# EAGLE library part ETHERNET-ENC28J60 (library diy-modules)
Ethernet Module based on ENC28J60 chip Click here to find device on ebay.com Note: There are many variants. Search for the proper version.

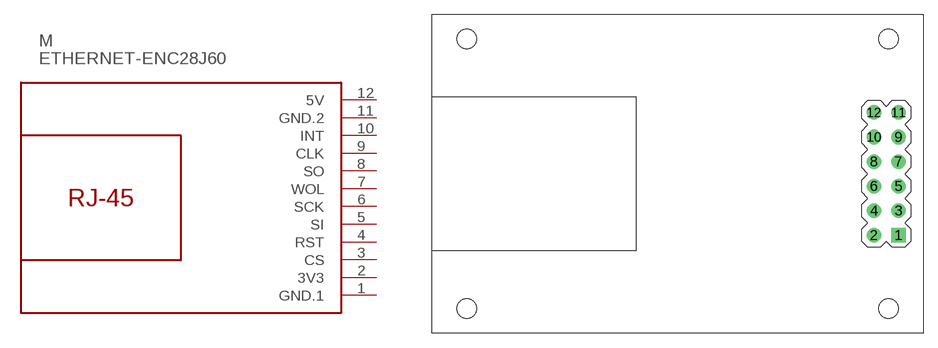
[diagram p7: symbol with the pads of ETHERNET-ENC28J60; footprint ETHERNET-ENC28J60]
Designator prefix M

## ETHERNET-ENC28J60  [ETHERNET-ENC28J60]
1  GND.1  pwr
2  3V3  pwr
3  CS
4  RST
5  SI
6  SCK
7  WOL
8  SO
9  CLK
10  INT
11  GND.2  pwr
12  5V  pwr

## Footprint ETHERNET-ENC28J60 (pad centres in mm)
Ethernet Module based on ENC28J60 chip
drill 1 square: 1 22.86,-6.35
drill 1: 2 20.32,-6.35; 3 22.86,-3.81; 4 20.32,-3.81; 5 22.86,-1.27; 6 20.32,-1.27; 7 22.86,1.27; 8 20.32,1.27; 9 22.86,3.81; 10 20.32,3.81; 11 22.86,6.35; 12 20.32,6.35
hole 2 at -21.844,13.97
hole 2 at 21.844,13.97
hole 2 at -21.844,-13.97
hole 2 at 21.844,-13.97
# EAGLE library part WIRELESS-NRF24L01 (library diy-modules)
2.4 GHz Wireless Module based on NRF24L01 chip More details available here: http://www.electrodragon.com/w/NRF24L01 Click here to find device on ebay.com

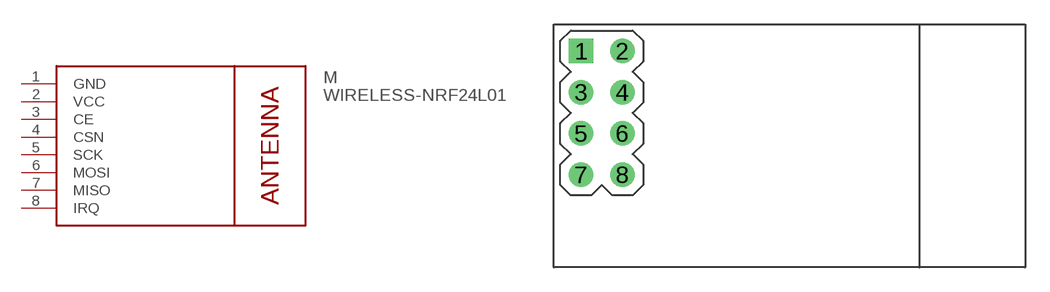
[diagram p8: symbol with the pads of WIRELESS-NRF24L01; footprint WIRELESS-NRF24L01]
Designator prefix M

## WIRELESS-NRF24L01  [WIRELESS-NRF24L01]
1  GND  pwr
2  VCC  pwr
3  CE
4  CSN
5  SCK
6  MOSI
7  MISO
8  IRQ

## Footprint WIRELESS-NRF24L01 (pad centres in mm)
2.4 GHz Wireless Module based on NRF24L01 chip
drill 1 square: 1 -12.7,6.35
drill 1: 2 -10.16,6.35; 3 -12.7,3.81; 4 -10.16,3.81; 5 -12.7,1.27; 6 -10.16,1.27; 7 -12.7,-1.27; 8 -10.16,-1.27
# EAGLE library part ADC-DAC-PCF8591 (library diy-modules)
4-Channel ADC and 1-Channel DAC Module based on PCF8591 chip More details available here: https://brainfyre.wordpress.com/2012/10/25/pcf8591-yl-40-ad-da-module-review/ Click here to find device on ebay.com

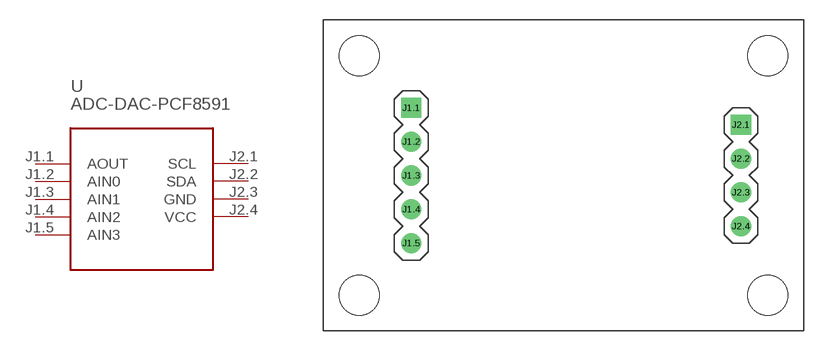
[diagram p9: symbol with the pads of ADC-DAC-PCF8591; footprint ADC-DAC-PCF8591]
Designator prefix -

## ADC-DAC-PCF8591  [ADC-DAC-PCF8591]
J1.1  AOUT
J1.2  AIN0
J1.3  AIN1
J1.4  AIN2
J1.5  AIN3
J2.1  SCL
J2.2  SDA
J2.3  GND  pwr
J2.4  VCC  pwr

## Footprint ADC-DAC-PCF8591 (pad centres in mm)
4-Channel ADC and 1-Channel DAC Module based on PCF8591 chip
drill 1 square: J1.1 -11.43,5.08; J2.1 13.335,3.81
drill 1: J1.2 -11.43,2.54; J1.3 -11.43,0; J1.4 -11.43,-2.54; J1.5 -11.43,-5.08; J2.2 13.335,1.27; J2.3 13.335,-1.27; J2.4 13.335,-3.81
hole 3 at -15.35,9
hole 3 at 15.35,9
hole 3 at -15.35,-9
hole 3 at 15.35,-9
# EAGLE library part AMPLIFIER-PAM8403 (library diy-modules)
Stereo Class-D 3W Audio Amplifier based on PAM8403 chip More details available here: http://artofcircuits.com/product/pam8403-5v-two-channel-stereo-mini-class-d-3w3w-audio-amplifier Click here to find device on ebay.com

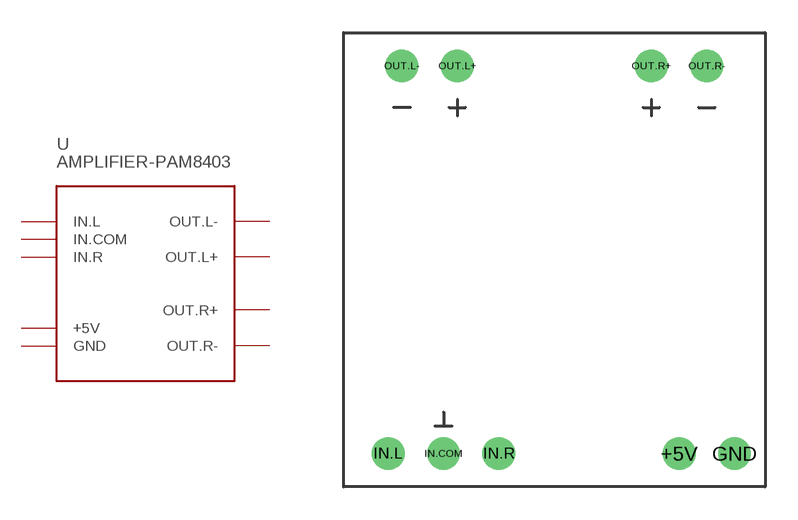
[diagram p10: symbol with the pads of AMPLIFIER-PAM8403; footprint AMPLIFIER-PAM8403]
Designator prefix -

## AMPLIFIER-PAM8403  [AMPLIFIER-PAM8403]
+5V  +5V  pwr
GND  GND  pwr
IN.COM  IN.COM  in
IN.L  IN.L  in
IN.R  IN.R
OUT.L+  OUT.L+  out
OUT.L-  OUT.L-  out
OUT.R+  OUT.R+  out
OUT.R-  OUT.R-  out

## Footprint AMPLIFIER-PAM8403 (pad centres in mm)
Stereo Class-D 3W Audio Amplifier based on PAM8403 chip
drill 1: +5V 5.715,-8.89; GND 8.255,-8.89; IN.COM -5.08,-8.89; IN.L -7.62,-8.89; IN.R -2.54,-8.89; OUT.L+ -4.445,8.89; OUT.L- -6.985,8.89; OUT.R+ 4.445,8.89; OUT.R- 6.985,8.89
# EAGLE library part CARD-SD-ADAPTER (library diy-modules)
Full Size SD Card Adapter Module with onboard 3.3V regulator Guide describing how to use SD card with Arduino is available here: https://www.arduino.cc/en/Reference/SDCardNotes Click here to find device on ebay.com

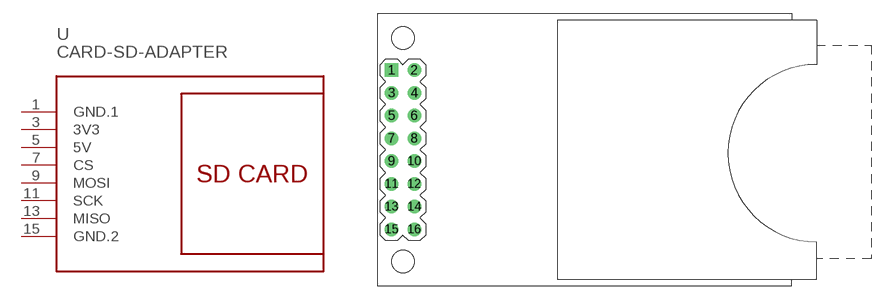
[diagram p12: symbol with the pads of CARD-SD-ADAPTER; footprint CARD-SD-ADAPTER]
Designator prefix -

## CARD-SD-ADAPTER  [CARD-SD-ADAPTER]
1  GND.1  pwr
3  3V3  pwr
5  5V  pwr
7  CS
9  MOSI
11  SCK
13  MISO
15  GND.2  pwr

## Footprint CARD-SD-ADAPTER (pad centres in mm)
Full Size SD Card Adapter Module with onboard 3.3V regulator
drill 1 square: 1 -21.59,8.89
drill 1: 2 -19.05,8.89; 3 -21.59,6.35; 4 -19.05,6.35; 5 -21.59,3.81; 6 -19.05,3.81; 7 -21.59,1.27; 8 -19.05,1.27; 9 -21.59,-1.27; 10 -19.05,-1.27; 11 -21.59,-3.81; 12 -19.05,-3.81; 13 -21.59,-6.35; 14 -19.05,-6.35; 15 -21.59,-8.89; 16 -19.05,-8.89
hole 2.5 at -20.32,12.5
hole 2.5 at -20.32,-12.5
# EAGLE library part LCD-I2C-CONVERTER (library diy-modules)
I2C Bus to 4-Bit Parallel LCD Interface with LED backlight driver

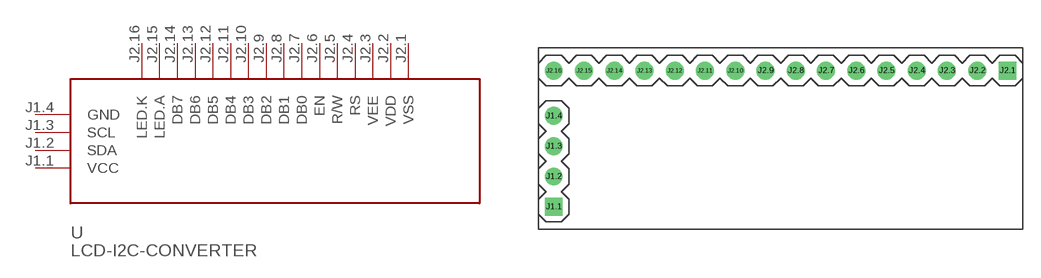
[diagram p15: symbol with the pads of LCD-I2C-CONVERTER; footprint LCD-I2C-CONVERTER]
Designator prefix -

## LCD-I2C-CONVERTER  [LCD-I2C-CONVERTER]
J1.1  VCC  pwr
J1.2  SDA
J1.3  SCL
J1.4  GND  pwr
J2.1  VSS
J2.2  VDD
J2.3  VEE
J2.4  RS
J2.5  R/W
J2.6  EN
J2.7  DB0
J2.8  DB1
J2.9  DB2
J2.10  DB3
J2.11  DB4
J2.12  DB5
J2.13  DB6
J2.14  DB7
J2.15  LED.A
J2.16  LED.K

## Footprint LCD-I2C-CONVERTER (pad centres in mm)
I2C Bus to 4-Bit Parallel LCD Interface with LED backlight driver
drill 1 square: J1.1 -19.05,-5.08; J2.1 19.05,6.35
drill 1: J1.2 -19.05,-2.54; J1.3 -19.05,0; J1.4 -19.05,2.54; J2.2 16.51,6.35; J2.3 13.97,6.35; J2.4 11.43,6.35; J2.5 8.89,6.35; J2.6 6.35,6.35; J2.7 3.81,6.35; J2.8 1.27,6.35; J2.9 -1.27,6.35; J2.10 -3.81,6.35; J2.11 -6.35,6.35; J2.12 -8.89,6.35; J2.13 -11.43,6.35; J2.14 -13.97,6.35; J2.15 -16.51,6.35; J2.16 -19.05,6.35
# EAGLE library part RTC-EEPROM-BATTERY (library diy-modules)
RTC Module with Battery and EEPROM based on DS1307 and AT24C32 chips More details available here: http://henrysbench.capnfatz.com/henrys-bench/arduino-sensors-and-input/arduino-tiny-rtc-d1307-tutorial/ Click here to find device on ebay.com

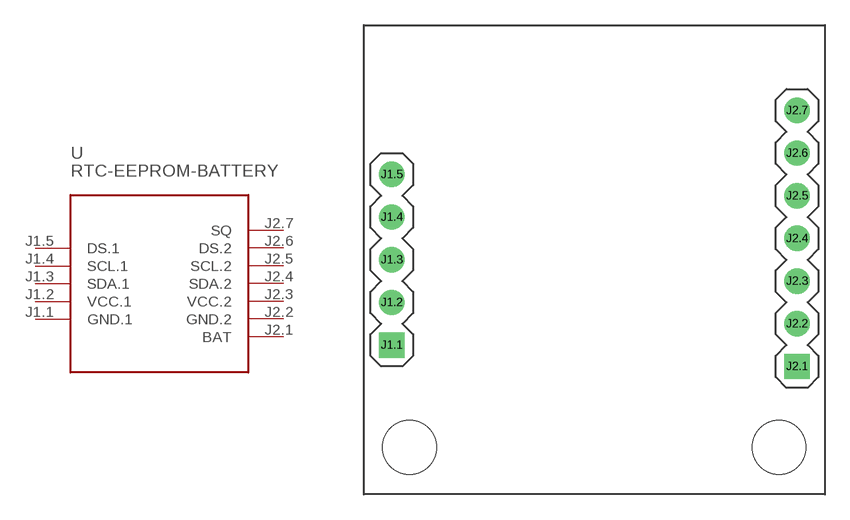
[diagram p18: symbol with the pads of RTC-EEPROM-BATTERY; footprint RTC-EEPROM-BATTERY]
Designator prefix -

## RTC-EEPROM-BATTERY  [RTC-EEPROM-BATTERY]
J1.1  GND.1  pwr
J1.2  VCC.1  pwr
J1.3  SDA.1
J1.4  SCL.1
J1.5  DS.1
J2.1  BAT
J2.2  GND.2  pwr
J2.3  VCC.2  pwr
J2.4  SDA.2
J2.5  SCL.2
J2.6  DS.2
J2.7  SQ

## Footprint RTC-EEPROM-BATTERY (pad centres in mm)
RTC Module with Battery and EEPROM based on DS1307 and AT24C32 chips
drill 1 square: J1.1 -12.065,-5.08; J2.1 12.065,-6.35
drill 1: J1.2 -12.065,-2.54; J1.3 -12.065,0; J1.4 -12.065,2.54; J1.5 -12.065,5.08; J2.2 12.065,-3.81; J2.3 12.065,-1.27; J2.4 12.065,1.27; J2.5 12.065,3.81; J2.6 12.065,6.35; J2.7 12.065,8.89
hole 3.2 at -11,-11.176
hole 3.2 at 11,-11.176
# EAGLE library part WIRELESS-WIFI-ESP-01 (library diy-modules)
Wireless Wi-Fi ESP-01 Module based on ESP8266 chip Click here to find device on ebay.com

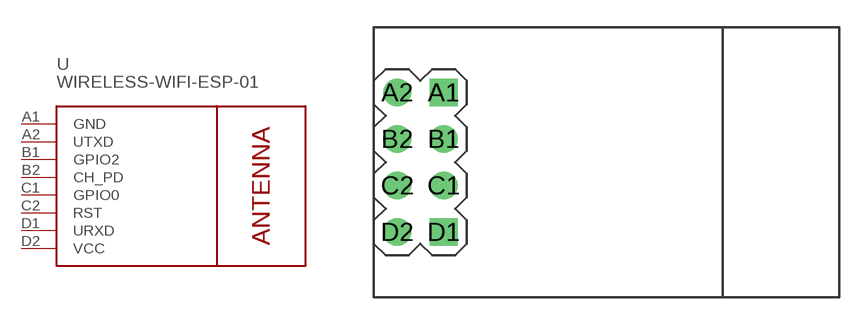
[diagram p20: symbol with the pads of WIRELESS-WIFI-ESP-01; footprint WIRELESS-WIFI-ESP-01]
Designator prefix -

## WIRELESS-WIFI-ESP-01  [WIRELESS-WIFI-ESP-01]
A1  GND  pwr
A2  UTXD
B1  GPIO2
B2  CH_PD
C1  GPIO0
C2  RST
D1  URXD
D2  VCC  pwr

## Footprint WIRELESS-WIFI-ESP-01 (pad centres in mm)
Wireless Wi-Fi ESP-01 Module based on ESP8266 chip
drill 1 square: A1 -8.89,3.81; D1 -8.89,-3.81
drill 1: A2 -11.43,3.81; B1 -8.89,1.27; B2 -11.43,1.27; C1 -8.89,-1.27; C2 -11.43,-1.27; D2 -11.43,-3.81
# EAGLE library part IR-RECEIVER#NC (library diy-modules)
IR Receiver Module without IR sensor connector

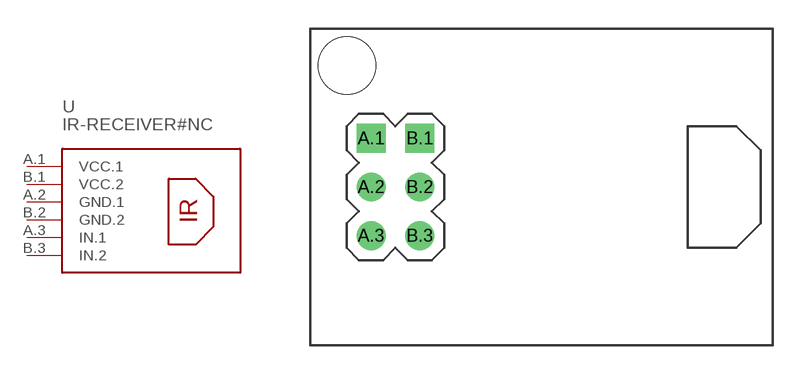
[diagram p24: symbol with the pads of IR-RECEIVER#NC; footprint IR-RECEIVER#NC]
Designator prefix -

## IR-RECEIVER#NC  [IR-RECEIVER#NC]
A.1  VCC.1
A.2  GND.1
A.3  IN.1
B.1  VCC.2
B.2  GND.2
B.3  IN.2

## Footprint IR-RECEIVER#NC (pad centres in mm)
IR Receiver Module Symbol wihtout IR sensor connector
drill 1 square: A.1 -8.89,2.54; B.1 -6.35,2.54
drill 1: A.2 -8.89,0; A.3 -8.89,-2.54; B.2 -6.35,0; B.3 -6.35,-2.54
hole 3 at -10.16,6.35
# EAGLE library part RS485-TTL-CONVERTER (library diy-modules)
RS485 to TTL converter based on MAX485 chip

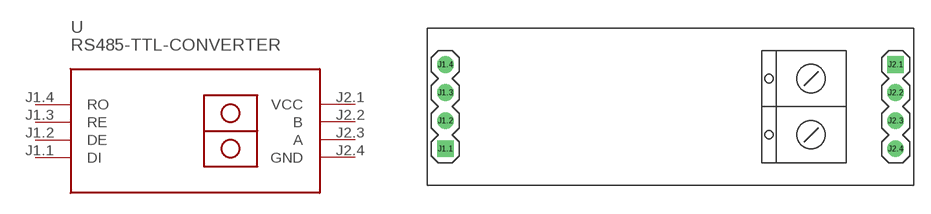
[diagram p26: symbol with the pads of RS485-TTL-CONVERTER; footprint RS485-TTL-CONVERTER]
Designator prefix -

## RS485-TTL-CONVERTER  [RS485-TTL-CONVERTER]
J1.1  DI  pas
J1.2  DE  pas
J1.3  RE  pas
J1.4  RO  pas
J2.1  VCC  pwr
J2.2  B  pas
J2.3  A  pas
J2.4  GND  pwr

## Footprint RS485-TTL-CONVERTER (pad centres in mm)
RS485 to TTL converter based on MAX485 chip
drill 1 square: J1.1 -20.32,-3.81; J2.1 20.32,3.81
drill 1: J1.2 -20.32,-1.27; J1.3 -20.32,1.27; J1.4 -20.32,3.81; J2.2 20.32,1.27; J2.3 20.32,-1.27; J2.4 20.32,-3.81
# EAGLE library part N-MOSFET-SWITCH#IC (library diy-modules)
Low Side N-MOSFET Switch with Optocoupler Device with connector pins Click here to find device on ebay.com

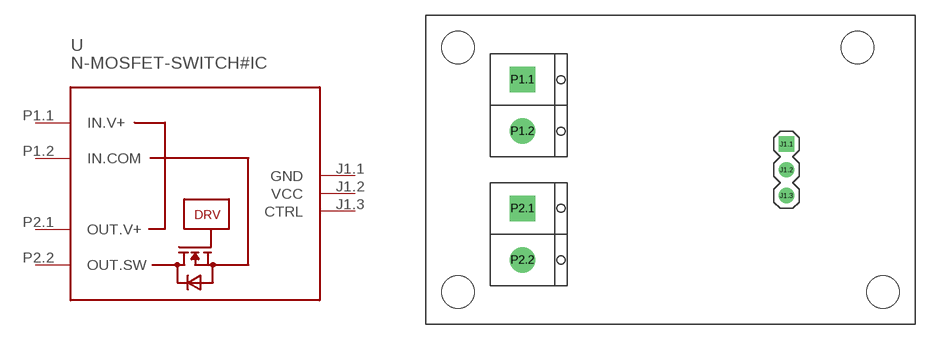
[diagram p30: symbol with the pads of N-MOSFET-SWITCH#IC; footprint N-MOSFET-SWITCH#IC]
Designator prefix -

## N-MOSFET-SWITCH#IC  [N-MOSFET-SWITCH#IC]
J1.1  GND  pwr
J1.2  VCC  pwr
J1.3  CTRL
P1.1  IN.V+  pwr
P1.2  IN.COM  pwr
P2.1  OUT.V+  pwr
P2.2  OUT.SW  pwr

## Footprint N-MOSFET-SWITCH#IC (pad centres in mm)
Low Side N-MOSFET Switch with Optocoupler Package with connector pins
drill 1 square: J1.1 11.43,2.54
drill 1: J1.2 11.43,0; J1.3 11.43,-2.54
drill 1.2 pad 2.5 square: P1.1 -14.605,8.89; P2.1 -14.605,-3.81
drill 1.2 pad 2.5: P1.2 -14.605,3.81; P2.2 -14.605,-8.89
hole 3.2 at -20.955,12.065
hole 3.2 at 18.415,12.065
hole 3.2 at 20.955,-12.065
hole 3.2 at -20.955,-12.065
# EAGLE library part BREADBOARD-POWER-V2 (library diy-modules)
Breadboard Power Adapter with onboard 3.3V and 5V regulators Click here to find device on ebay.com

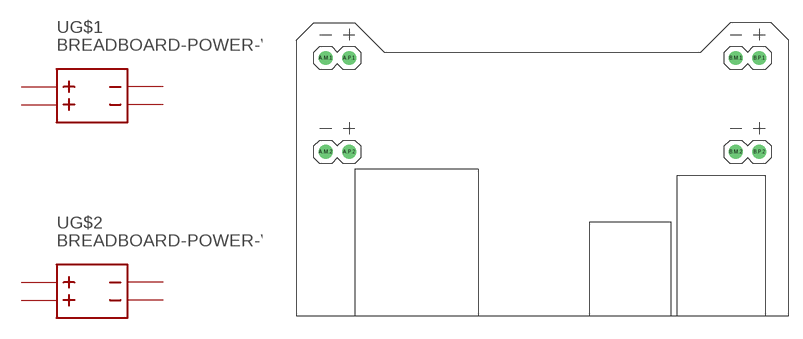
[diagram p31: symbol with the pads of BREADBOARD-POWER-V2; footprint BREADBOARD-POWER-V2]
Designator prefix -; gates G$1=BREADBOARD-POWER-V2 G$2=BREADBOARD-POWER-V2

## BREADBOARD-POWER-V2  [BREADBOARD-POWER-V2]
A.M.1  G$1:M.1
A.M.2  G$1:M.2
A.P.1  G$1:P.1
A.P.2  G$1:P.2
B.M.1  G$2:M.1
B.M.2  G$2:M.2
B.P.1  G$2:P.1
B.P.2  G$2:P.2

## Footprint BREADBOARD-POWER-V2 (pad centres in mm)
Breadboard Power Adapter with onboard 3.3V and 5V regulators
drill 1: A.M.1 -23.495,12.065; A.M.2 -23.495,1.905; A.P.1 -20.955,12.065; A.P.2 -20.955,1.905; B.M.1 20.955,12.065; B.M.2 20.955,1.905; B.P.1 23.495,12.065; B.P.2 23.495,1.905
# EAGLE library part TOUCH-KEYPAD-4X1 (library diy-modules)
4 Channel Capacitive Touch Keypad Click here to find device on ebay.com

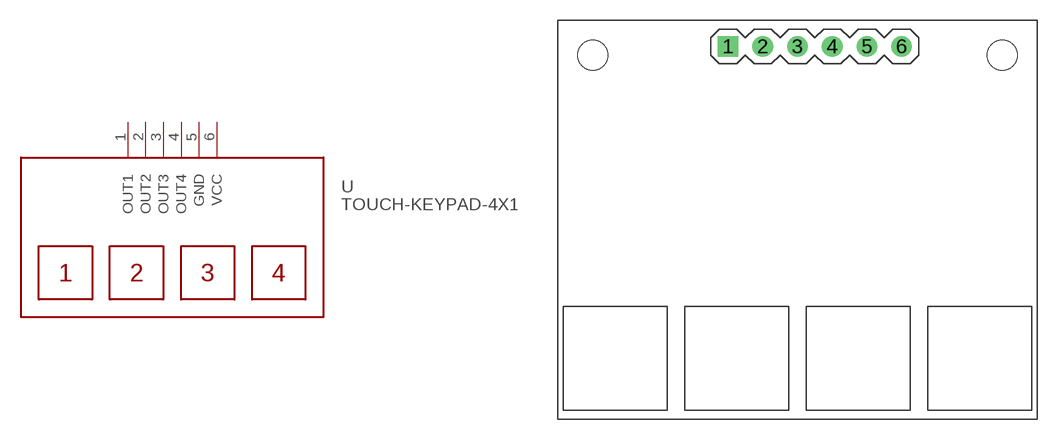
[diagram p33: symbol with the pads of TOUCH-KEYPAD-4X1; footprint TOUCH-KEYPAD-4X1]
Designator prefix -

## TOUCH-KEYPAD-4X1  [TOUCH-KEYPAD-4X1]
1  OUT1
2  OUT2
3  OUT3
4  OUT4
5  GND  pwr
6  VCC  pwr

## Footprint TOUCH-KEYPAD-4X1 (pad centres in mm)
4 Channel Capacitive Touch Keypad
drill 1 square: 1 -5.08,12.7
drill 1: 2 -2.54,12.7; 3 0,12.7; 4 2.54,12.7; 5 5.08,12.7; 6 7.62,12.7
hole 2.2 at -14.986,12.065
hole 2.2 at 14.986,12.065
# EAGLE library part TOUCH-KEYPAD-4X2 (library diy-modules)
8 Channel Capacitive Touch Keypad Click here to find device on ebay.com

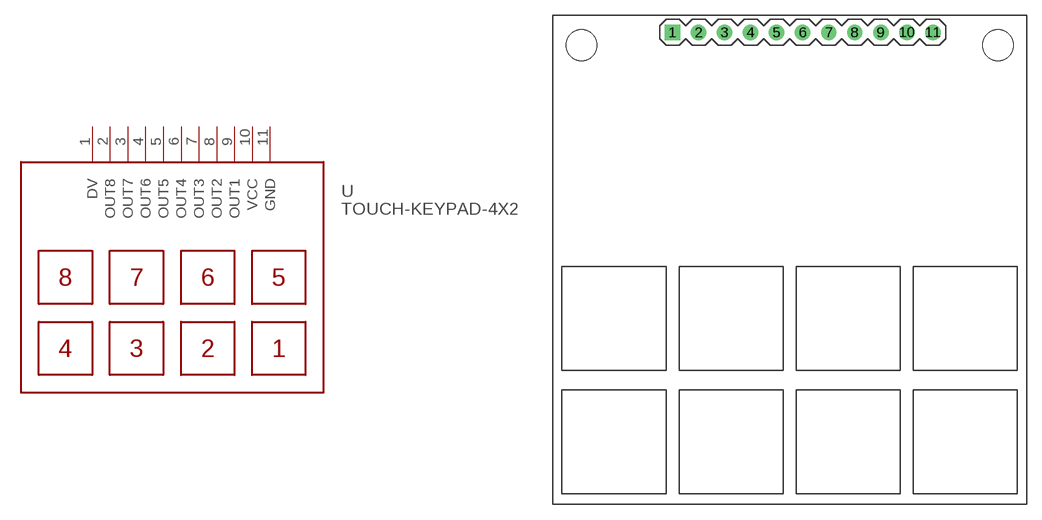
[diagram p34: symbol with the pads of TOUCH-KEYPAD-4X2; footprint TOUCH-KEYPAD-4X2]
Designator prefix -

## TOUCH-KEYPAD-4X2  [TOUCH-KEYPAD-4X2]
1  DV
2  OUT8
3  OUT7
4  OUT6
5  OUT5
6  OUT4
7  OUT3
8  OUT2
9  OUT1
10  VCC  pwr
11  GND  pwr

## Footprint TOUCH-KEYPAD-4X2 (pad centres in mm)
8 Channel Capacitive Touch Keypad
drill 1 square: 1 -11.43,22.225
drill 1: 2 -8.89,22.225; 3 -6.35,22.225; 4 -3.81,22.225; 5 -1.27,22.225; 6 1.27,22.225; 7 3.81,22.225; 8 6.35,22.225; 9 8.89,22.225; 10 11.43,22.225; 11 13.97,22.225
hole 3 at -20.32,20.955
hole 3 at 20.32,20.955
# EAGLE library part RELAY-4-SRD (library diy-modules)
4-Channel Relay Module based on SRD-05VDC-SL-C relays Click here to find device on ebay.com

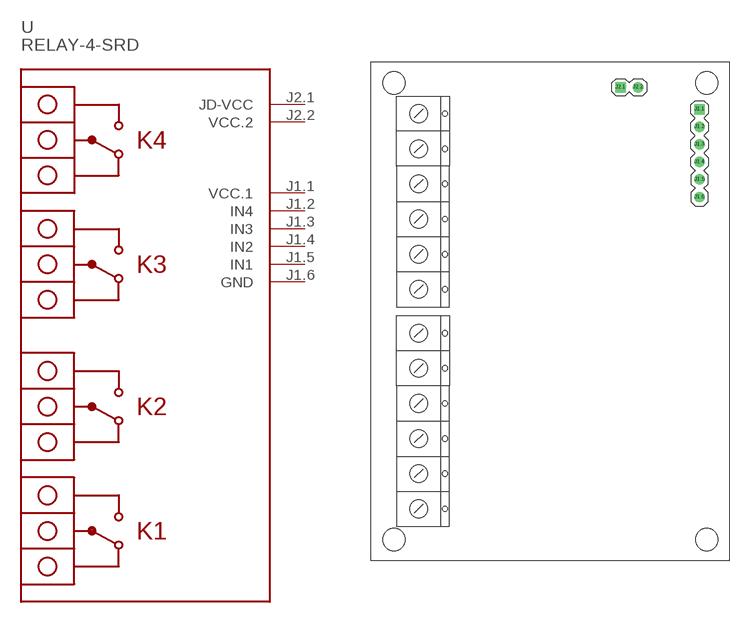
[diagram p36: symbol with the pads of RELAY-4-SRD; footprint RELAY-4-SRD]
Designator prefix -

## RELAY-4-SRD  [RELAY-4-SRD]
J1.1  VCC.1  pwr
J1.2  IN4
J1.3  IN3
J1.4  IN2
J1.5  IN1
J1.6  GND  pwr
J2.1  JD-VCC
J2.2  VCC.2  pwr

## Footprint RELAY-4-SRD (pad centres in mm)
4-Channel Relay Module based on SRD-05VDC-SL-C relays
drill 1 square: J1.1 21.59,29.21; J2.1 10.16,32.385
drill 1: J1.2 21.59,26.67; J1.3 21.59,24.13; J1.4 21.59,21.59; J1.5 21.59,19.05; J1.6 21.59,16.51; J2.2 12.7,32.385
hole 3.2 at -22.606,33.02
hole 3.2 at 22.606,33.02
hole 3.2 at 22.606,-33.02
hole 3.2 at -22.606,-33.02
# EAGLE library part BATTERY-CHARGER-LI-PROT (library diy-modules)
Lithium Battery 5V Charger with protection circuit More details available here: http://www.instructables.com/id/DIY-Lithium-ion-Battery-Charger/step4/TP4056-based-lithium-ion-battery-charger-module/ Click here to find device on ebay.com

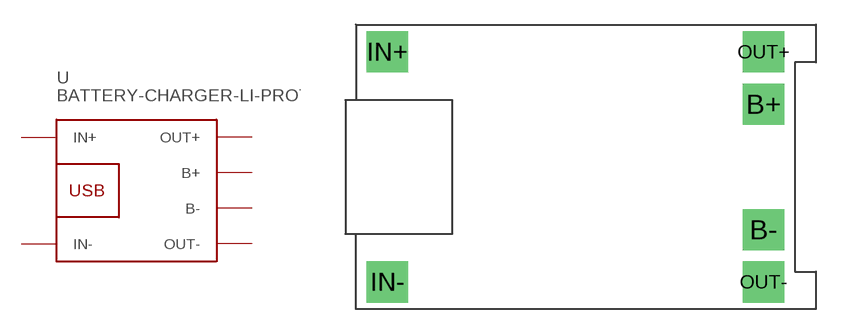
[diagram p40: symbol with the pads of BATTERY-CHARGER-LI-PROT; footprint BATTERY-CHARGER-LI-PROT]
Designator prefix -

## BATTERY-CHARGER-LI-PROT  [BATTERY-CHARGER-LI-PROT]
B+  B+
B-  B-
IN+  IN+
IN-  IN-
OUT+  OUT+
OUT-  OUT-

## Footprint BATTERY-CHARGER-LI-PROT (pad centres in mm)
Protected Lithium Battery 5V Charger with micro-USB connector
drill 1.2 pad 2.5 square: B+ 10.795,3.81; B- 10.795,-3.81; IN+ -12.065,6.985; IN- -12.065,-6.985; OUT+ 10.795,6.985; OUT- 10.795,-6.985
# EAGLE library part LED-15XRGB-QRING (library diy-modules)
15 LEDs RGB Quarter-Ring based on WS2812B More details about controlling WS2812B RGB LEDs are available here: https://learn.sparkfun.com/tutorials/ws2812-breakout-hookup-guide Click here to find device on ebay.com Note: Sold in packs of 4 pieces.

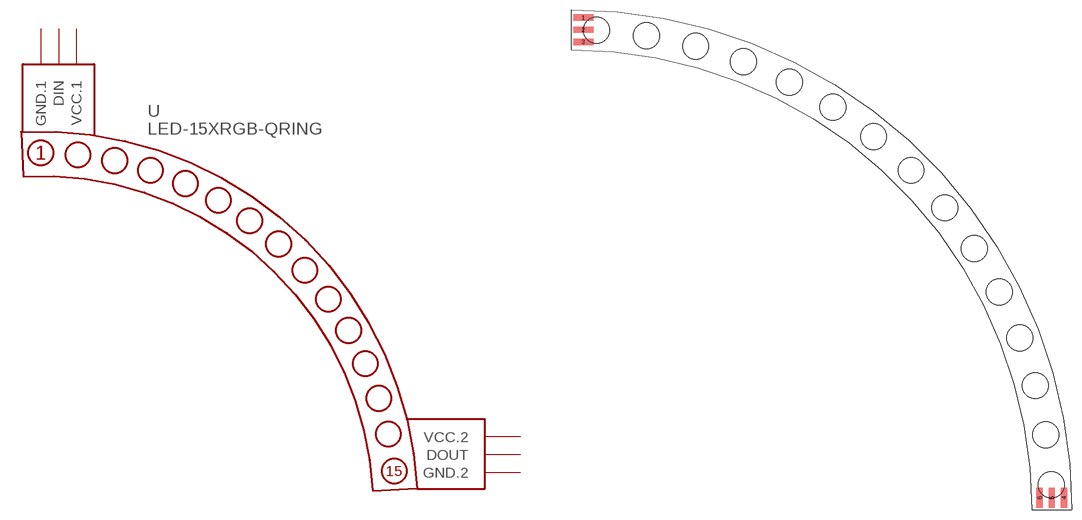
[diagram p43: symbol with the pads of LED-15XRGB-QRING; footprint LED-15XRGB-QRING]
Designator prefix -

## LED-15XRGB-QRING  [LED-15XRGB-QRING]
1  GND.1  pwr
2  DIN  in
3  VCC.1  pwr
4  GND.2  pwr
5  DOUT  out
6  VCC.2  pwr

## Footprint LED-15XRGB-QRING (pad centres in mm)
15 LEDs RGB Quarter-Ring based on WS2812B
smd 3.175 x 1.016: 1 1.905,77.47; 2 1.905,75.565; 3 1.905,73.66
smd 1.016 x 3.175: 4 77.47,1.905; 5 75.565,1.905; 6 73.66,1.905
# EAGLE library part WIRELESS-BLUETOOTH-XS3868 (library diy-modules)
Bluetooth Stereo Audio Module based on OVC3860 chip More details available here: http://artofcircuits.com/product/bluetooth-2-0-edr-stereo-audio-ovc3860-module-model-xs-3868 Click here to find device on ebay.com

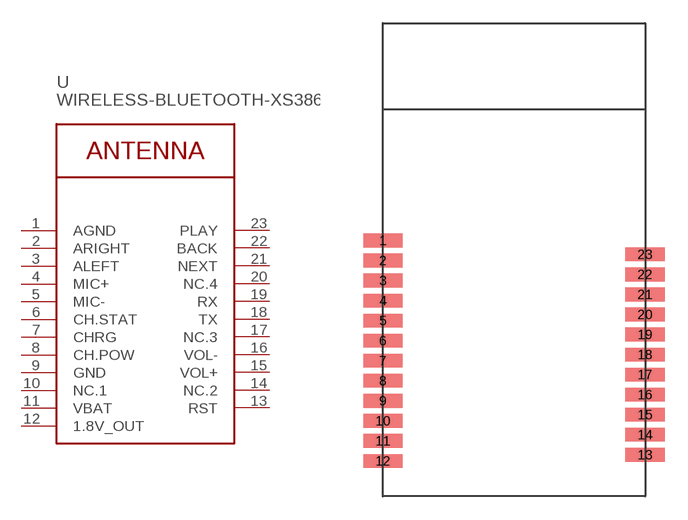
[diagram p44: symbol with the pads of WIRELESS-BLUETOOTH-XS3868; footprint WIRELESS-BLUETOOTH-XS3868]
Designator prefix -

## WIRELESS-BLUETOOTH-XS3868  [WIRELESS-BLUETOOTH-XS3868]
1  AGND  pwr
2  ARIGHT  out
3  ALEFT  out
4  MIC+
5  MIC-
6  CH.STAT
7  CHRG
8  CH.POW
9  GND  pwr
10  NC.1  pas
11  VBAT  pwr
12  1.8V_OUT  pwr
13  RST  pwr
14  NC.2  pas
15  VOL+
16  VOL-
17  NC.3  pas
18  TX
19  RX
20  NC.4  pas
21  NEXT
22  BACK
23  PLAY

## Footprint WIRELESS-BLUETOOTH-XS3868 (pad centres in mm)
Bluetooth Stereo Audio Module based on OVC3860 chip
smd 2.54 x 0.889: 1 -8.5,0.995; 2 -8.5,-0.305; 3 -8.5,-1.605; 4 -8.5,-2.905; 5 -8.5,-4.205; 6 -8.5,-5.505; 7 -8.5,-6.805; 8 -8.5,-8.105; 9 -8.5,-9.405; 10 -8.5,-10.705; 11 -8.5,-12.005; 12 -8.5,-13.305; 13 8.5,-12.905; 14 8.5,-11.605; 15 8.5,-10.305; 16 8.5,-9.005; 17 8.5,-7.705; 18 8.5,-6.405; 19 8.5,-5.105; 20 8.5,-3.805; 21 8.5,-2.505; 22 8.5,-1.205; 23 8.5,0.095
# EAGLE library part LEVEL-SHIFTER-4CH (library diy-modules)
4-Channel Bi-Directional Logic Level Converter based on BSS128 transistors Click here to find device on ebay.com

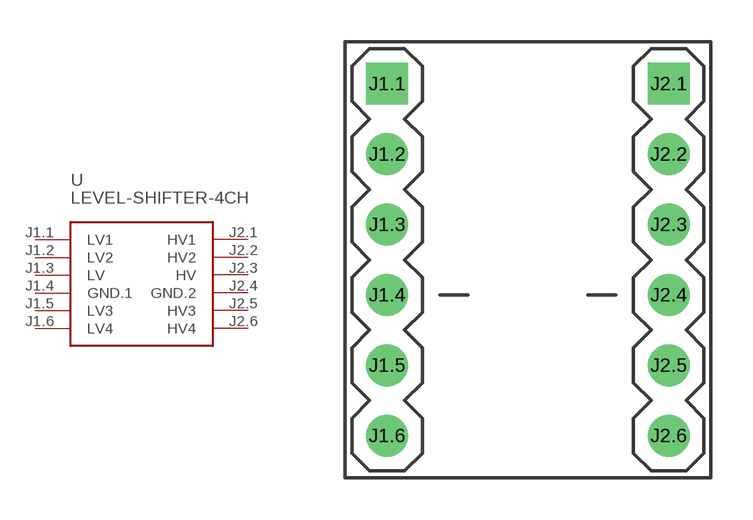
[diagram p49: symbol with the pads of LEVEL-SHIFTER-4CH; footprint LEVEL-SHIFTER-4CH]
Designator prefix -

## LEVEL-SHIFTER-4CH  [LEVEL-SHIFTER-4CH]
J1.1  LV1
J1.2  LV2
J1.3  LV  pwr
J1.4  GND.1  pwr
J1.5  LV3
J1.6  LV4
J2.1  HV1
J2.2  HV2
J2.3  HV  pwr
J2.4  GND.2  pwr
J2.5  HV3
J2.6  HV4

## Footprint LEVEL-SHIFTER-4CH (pad centres in mm)
4-Channel Bi-Directional Logic Level Converter based on BSS128 transistors
drill 1 square: J1.1 -5.08,6.35; J2.1 5.08,6.35
drill 1: J1.2 -5.08,3.81; J1.3 -5.08,1.27; J1.4 -5.08,-1.27; J1.5 -5.08,-3.81; J1.6 -5.08,-6.35; J2.2 5.08,3.81; J2.3 5.08,1.27; J2.4 5.08,-1.27; J2.5 5.08,-3.81; J2.6 5.08,-6.35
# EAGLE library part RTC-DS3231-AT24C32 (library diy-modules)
RTC Module with Battery and EEPROM based on DS3231 and AT24C32 chips Tutorial can be found here: https://edwardmallon.wordpress.com/2014/05/21/using-a-cheap-3-ds3231-rtc-at24c32-eeprom-from-ebay/ Click here to find device on ebay.com

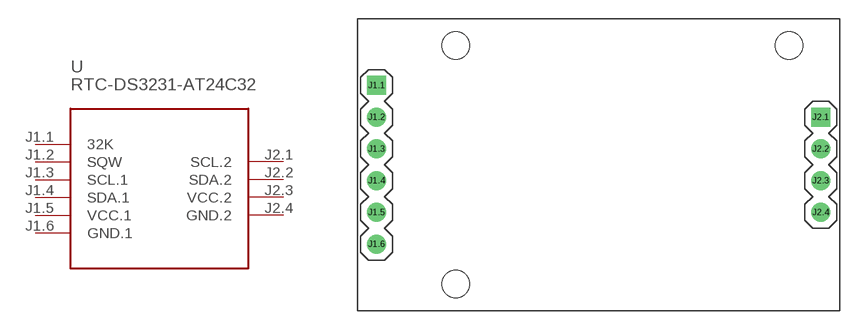
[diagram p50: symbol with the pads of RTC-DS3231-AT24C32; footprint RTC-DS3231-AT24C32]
Designator prefix -

## RTC-DS3231-AT24C32  [RTC-DS3231-AT24C32]
J1.1  32K
J1.2  SQW
J1.3  SCL.1
J1.4  SDA.1
J1.5  VCC.1  pwr
J1.6  GND.1  pwr
J2.1  SCL.2
J2.2  SDA.2
J2.3  VCC.2  pwr
J2.4  GND.2  pwr

## Footprint RTC-DS3231-AT24C32 (pad centres in mm)
RTC Module with Battery and EEPROM based on DS3231 and AT24C32 chips
drill 1 square: J1.1 -17.78,6.35; J2.1 17.78,3.81
drill 1: J1.2 -17.78,3.81; J1.3 -17.78,1.27; J1.4 -17.78,-1.27; J1.5 -17.78,-3.81; J1.6 -17.78,-6.35; J2.2 17.78,1.27; J2.3 17.78,-1.27; J2.4 17.78,-3.81
hole 2.2 at -11.43,-9.525
hole 2.2 at -11.43,9.525
hole 2.2 at 15.24,9.525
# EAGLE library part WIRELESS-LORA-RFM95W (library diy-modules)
868/915 MHz LoRa Radio Transceiver Module based on SX1276 chip Click here to find device on ebay.com

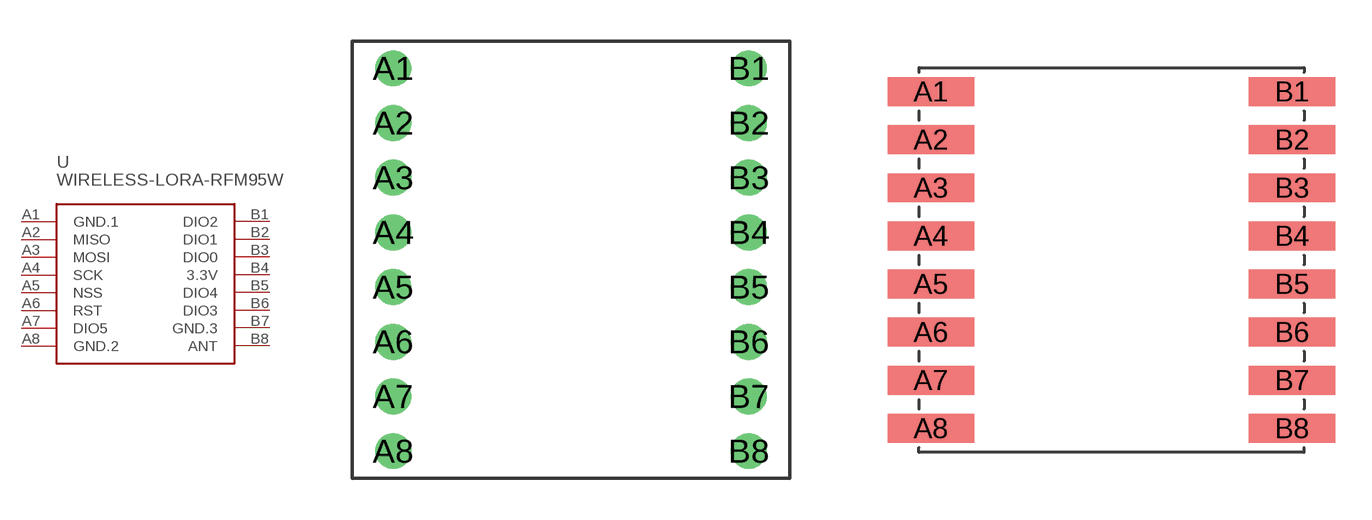
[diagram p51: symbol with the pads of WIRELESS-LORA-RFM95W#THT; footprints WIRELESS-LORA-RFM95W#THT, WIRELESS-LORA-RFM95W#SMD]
Designator prefix -

## WIRELESS-LORA-RFM95W#THT  [WIRELESS-LORA-RFM95W#THT]
A1  GND.1  pwr
A2  MISO
A3  MOSI
A4  SCK
A5  NSS
A6  RST
A7  DIO5
A8  GND.2  pwr
B1  DIO2
B2  DIO1
B3  DIO0
B4  3.3V  pwr
B5  DIO4
B6  DIO3
B7  GND.3  pwr
B8  ANT  pas

## WIRELESS-LORA-RFM95W#SMD  [WIRELESS-LORA-RFM95W#SMD]
Pads as for WIRELESS-LORA-RFM95W#THT

## Footprint WIRELESS-LORA-RFM95W#THT (pad centres in mm)
868/915 MHz LoRa Radio Transceiver Module Footprint for THT assembly.
drill 0.8: A1 -6.5,7; A2 -6.5,5; A3 -6.5,3; A4 -6.5,1; A5 -6.5,-1; A6 -6.5,-3; A7 -6.5,-5; A8 -6.5,-7; B1 6.5,7; B2 6.5,5; B3 6.5,3; B4 6.5,1; B5 6.5,-1; B6 6.5,-3; B7 6.5,-5; B8 6.5,-7

## Footprint WIRELESS-LORA-RFM95W#SMD (pad centres in mm)
868/915 MHz LoRa Radio Transceiver Module Footprint for SMD assembly.
smd 3.6 x 1.2: A1 -7.5,7; A2 -7.5,5; A3 -7.5,3; A4 -7.5,1; A5 -7.5,-1; A6 -7.5,-3; A7 -7.5,-5; A8 -7.5,-7; B1 7.5,7; B2 7.5,5; B3 7.5,3; B4 7.5,1; B5 7.5,-1; B6 7.5,-3; B7 7.5,-5; B8 7.5,-7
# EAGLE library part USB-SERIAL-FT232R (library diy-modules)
USB to Serial UART Converter based on FT232R chip More information about FT232R chip is available here: http://www.ftdichip.com/Products/ICs/FT232R.htm Click here to find device on ebay.com

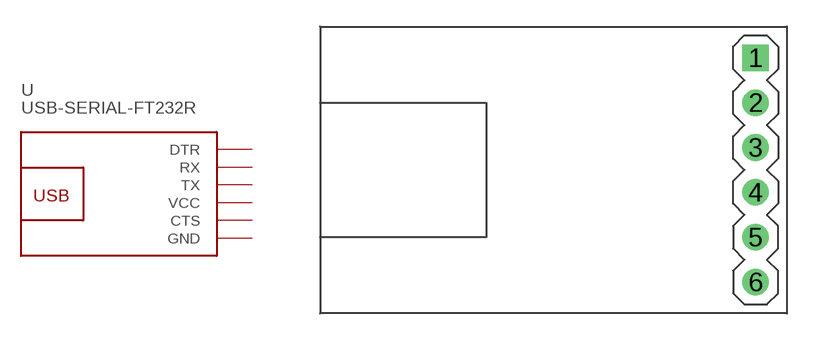
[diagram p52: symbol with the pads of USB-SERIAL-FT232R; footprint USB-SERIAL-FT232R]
Designator prefix -

## USB-SERIAL-FT232R  [USB-SERIAL-FT232R]
1  DTR
2  RX
3  TX
4  VCC  pwr
5  CTS
6  GND

## Footprint USB-SERIAL-FT232R (pad centres in mm)
USB to Serial UART Converter based on FT232R chip
drill 1 square: 1 11.43,6.35
drill 1: 2 11.43,3.81; 3 11.43,1.27; 4 11.43,-1.27; 5 11.43,-3.81; 6 11.43,-6.35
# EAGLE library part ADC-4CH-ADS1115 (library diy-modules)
4 Channel 16-Bit Analog-to-Digital Converter based on ADS1115 chip Arduino ADS1115 Getting Started Tutorial is available here: http://henrysbench.capnfatz.com/henrys-bench/arduino-voltage-measurements/arduino-ads1115-module-getting-started-tutorial/ ADS1115 datasheet is available here: http://www.ti.com/lit/ds/symlink/ads1115.pdf Click here to find device on ebay.com

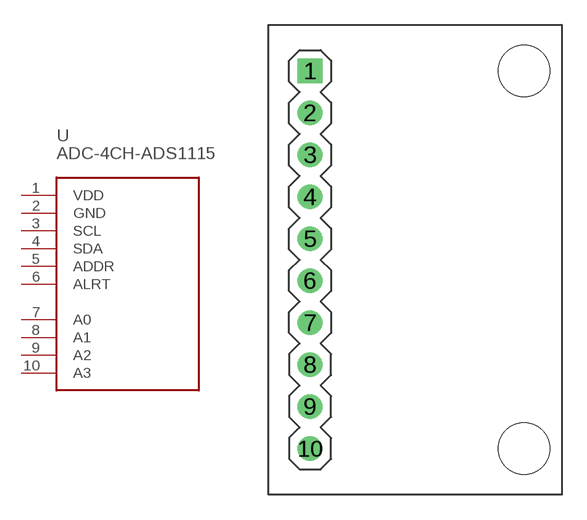
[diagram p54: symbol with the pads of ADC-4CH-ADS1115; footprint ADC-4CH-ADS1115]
Designator prefix -

## ADC-4CH-ADS1115  [ADC-4CH-ADS1115]
1  VDD  pwr
2  GND  pwr
3  SCL
4  SDA
5  ADDR
6  ALRT
7  A0  in
8  A1  in
9  A2  in
10  A3  in

## Footprint ADC-4CH-ADS1115 (pad centres in mm)
4 Channel 16-Bit Analog-to-Digital Converter based on ADS1115 chip
drill 1 square: 1 -6.35,11.43
drill 1: 2 -6.35,8.89; 3 -6.35,6.35; 4 -6.35,3.81; 5 -6.35,1.27; 6 -6.35,-1.27; 7 -6.35,-3.81; 8 -6.35,-6.35; 9 -6.35,-8.89; 10 -6.35,-11.43
hole 3.1 at 6.604,11.43
hole 3.1 at 6.604,-11.43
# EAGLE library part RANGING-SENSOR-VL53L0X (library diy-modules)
Laser Ranging Sensor based on VL53L0X device More information about VL53L0X device can be found here: http://www.st.com/en/imaging-and-photonics-solutions/vl53l0x.html Arduino Library for VL53L0X is available here: https://github.com/pololu/vl53l0x-arduino Click here to find device on ebay.com Note: There are many variants. Search for the proper version.

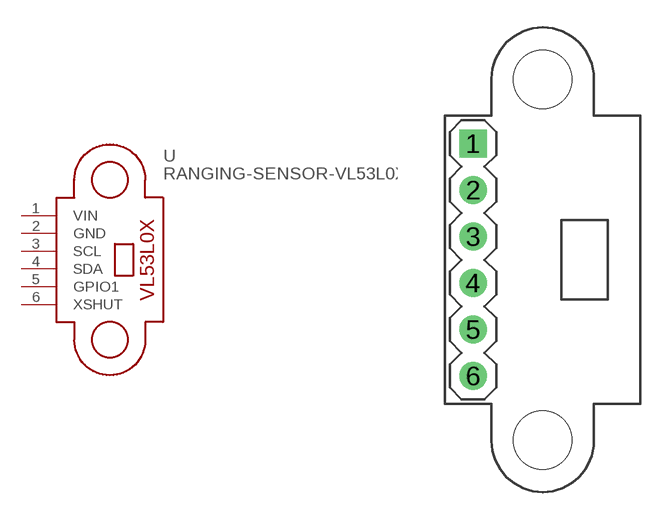
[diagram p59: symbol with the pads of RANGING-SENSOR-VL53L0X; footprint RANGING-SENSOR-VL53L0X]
Designator prefix -

## RANGING-SENSOR-VL53L0X  [RANGING-SENSOR-VL53L0X]
1  VIN  pwr
2  GND  pwr
3  SCL
4  SDA
5  GPIO1
6  XSHUT

## Footprint RANGING-SENSOR-VL53L0X (pad centres in mm)
Laser Ranging Sensor based on VL53L0X device
drill 1 square: 1 -3.81,6.35
drill 1: 2 -3.81,3.81; 3 -3.81,1.27; 4 -3.81,-1.27; 5 -3.81,-3.81; 6 -3.81,-6.35
hole 3.2 at 0,9.85
hole 3.2 at 0,-9.85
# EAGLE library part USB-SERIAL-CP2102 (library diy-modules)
USB to Serial UART Converter based on CP2102 chip More information about CP2102 chip is available here: https://www.silabs.com/documents/public/data-sheets/CP2102-9.pdf Drivers for CP210x devices are available here: http://www.silabs.com/products/development-tools/software/usb-to-uart-bridge-vcp-drivers Click here to find device on ebay.com

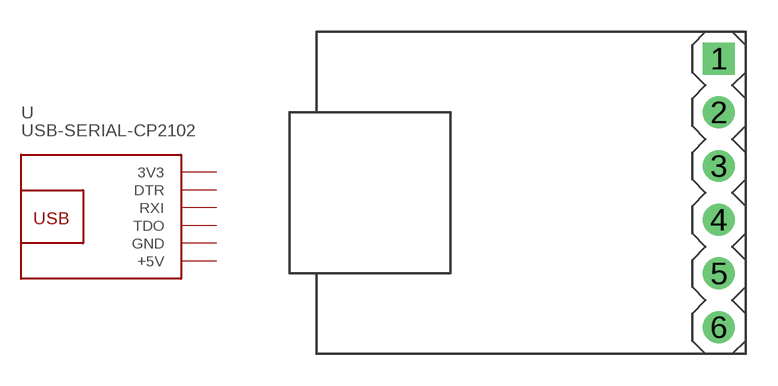
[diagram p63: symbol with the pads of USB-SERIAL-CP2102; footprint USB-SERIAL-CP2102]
Designator prefix -

## USB-SERIAL-CP2102  [USB-SERIAL-CP2102]
1  3V3  pwr
2  DTR
3  RXI
4  TDO
5  GND  pwr
6  +5V  pwr

## Footprint USB-SERIAL-CP2102 (pad centres in mm)
USB to Serial UART Converter based on CP2102 chip
drill 1 square: 1 8.89,6.35
drill 1: 2 8.89,3.81; 3 8.89,1.27; 4 8.89,-1.27; 5 8.89,-3.81; 6 8.89,-6.35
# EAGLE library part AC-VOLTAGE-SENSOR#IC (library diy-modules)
Isolated AC Voltage Sensor based on ZMPT101B transformer Symbol with input connector ZMPT101B Voltage Transformer Operating Guide is available here: http://www.zeming-e.com/file/0_2013_10_18_093344.pdf Click here to find device on ebay.com

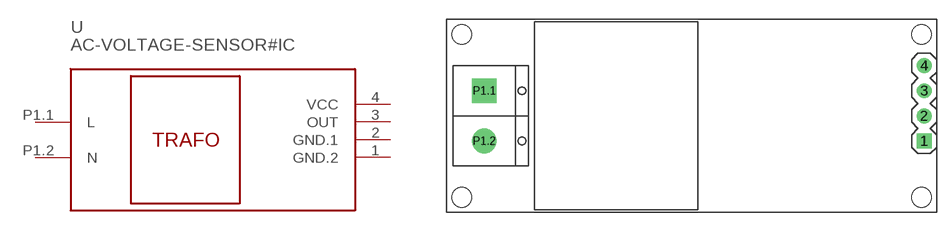
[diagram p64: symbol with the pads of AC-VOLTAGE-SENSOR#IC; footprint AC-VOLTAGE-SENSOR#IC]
Designator prefix -

## AC-VOLTAGE-SENSOR#IC  [AC-VOLTAGE-SENSOR#IC]
1  GND.2  pwr
2  GND.1  pwr
3  OUT  out
4  VCC  pwr
P1.1  L  pas
P1.2  N  pas

## Footprint AC-VOLTAGE-SENSOR#IC (pad centres in mm)
Isolated AC Voltage Sensor based on ZMPT101B transformer Footprint with input connector
drill 1 square: 1 23.495,-2.54
drill 1: 2 23.495,0; 3 23.495,2.54; 4 23.495,5.08
drill 1.2 pad 2.5 square: P1.1 -20.955,2.54
drill 1.2 pad 2.5: P1.2 -20.955,-2.54
hole 2 at -23.241,8.255
hole 2 at -23.241,-8.255
hole 2 at 23.241,-8.255
hole 2 at 23.241,8.255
